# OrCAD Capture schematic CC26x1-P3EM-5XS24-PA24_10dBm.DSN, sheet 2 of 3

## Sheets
2 CC26x1-P3EM-5XS24-PA24: size A4

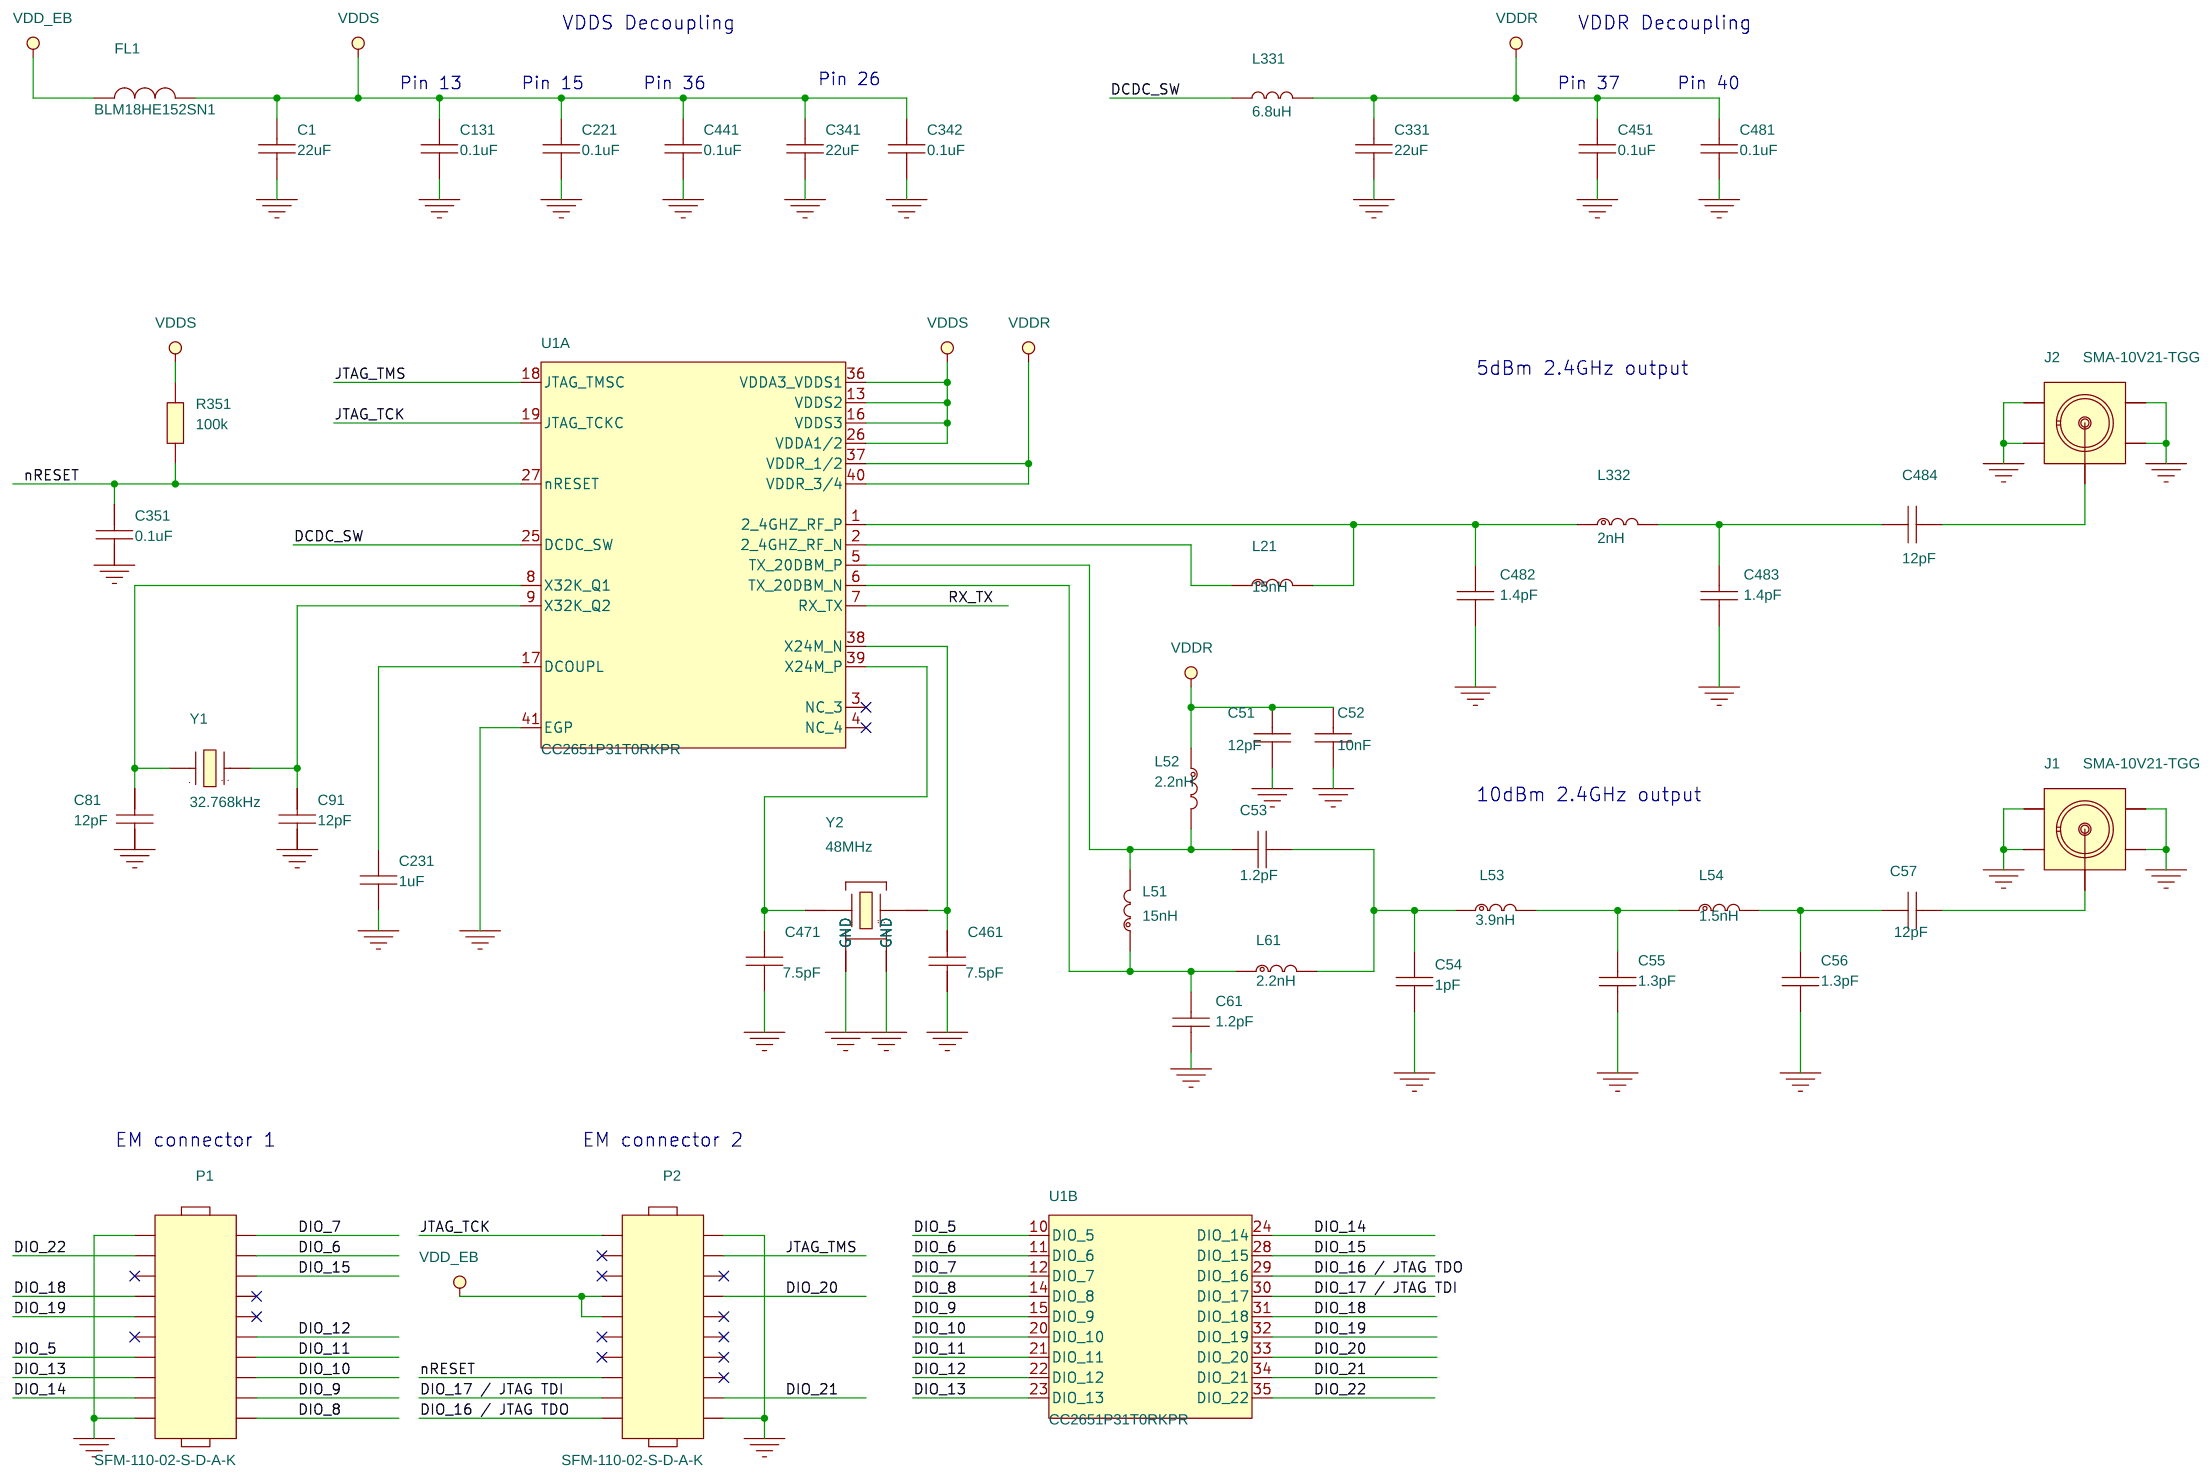
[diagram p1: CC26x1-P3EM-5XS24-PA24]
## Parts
C1  22uF  [CAPC1608X100A2N]
C51  12pF  [CAPC1005X60B2N]
C52  10nF  [CAPC1005X60B2N]
C53  1.2pF  [CAPC1005X60B2N]
C54  1pF  [CAPC1005X60B2N]
C55  1.3pF  [CAPC1005X60B2N]
C56  1.3pF  [CAPC1005X60B2N]
C57  12pF  [CAPC1005X60B2N]
C61  1.2pF  [CAPC1005X60B2N]
C81  12pF  [CAPC1005X60B2N]
C91  12pF  [CAPC1005X60B2N]
C131  0.1uF  [CAPC1005X60B2N]
C221  0.1uF  [CAPC1005X60B2N]
C231  1uF  [CAPC1005X60B2N]
C331  22uF  [CAPC1608X100A2N]
C341  22uF  [CAPC1608X100A2N]
C342  0.1uF  [CAPC1005X60B2N]
C351  0.1uF  [CAPC1005X60B2N]
C441  0.1uF  [CAPC1005X60B2N]
C451  0.1uF  [CAPC1005X60B2N]
C461  7.5pF  [CAPC1005X60B2N]
C471  7.5pF  [CAPC1005X60B2N]
C481  0.1uF  [CAPC1005X60B2N]
C482  1.4pF  [CAPC1005X60B2N]
C483  1.4pF  [CAPC1005X60B2N]
C484  12pF  [CAPC1005X60B2N]
FL1  BLM18HE152SN1  [FIL_BLM18HE152SN1DN]
J1  SMA-10V21-TGG  [HUSTSAN_SMA10V21TGGAN]
J2  SMA-10V21-TGG  [HUSTSAN_SMA10V21TGGAN]
L21  15nH  [INDC1005X60C2N]
L51  15nH  [INDC1005X60C2N]
L52  2.2nH  [INDC1005X60D2N]
L53  3.9nH  [INDC1005X60D2N]
L54  1.5nH  [INDC1005X60D2N]
L61  2.2nH  [INDC1005X60D2N]
L331  6.8uH  [INDC2012X150A2N]
L332  2nH  [INDC1005X60D2N]
P1  SFM-110-02-S-D-A-K  [SAMTEC_SFM11002AN]
P2  SFM-110-02-S-D-A-K  [SAMTEC_SFM11002AN]
R351  100k  [RESC1005X40B2N]
U1  CC2651P31T0RKPR  [QFNFC40P500X500X100-41A2N]  (sections A,B)
Y1  32.768kHz  [XTAL_TZ1166C_B2N]
Y2  48MHz  [OSCCC200X160X50-4A2N]

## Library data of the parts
C1 C331 C341 = CAPACITOR: CAPACITOR, CERAMIC X6S, 22uF, 6.3V, -20%/+20%, -55DEGC/+105DEGC, 0603, SMD; ALT_SYMBOLS: CAPC1608X100A2L,CAPC1608X100A2M; Additional Datasheet URL: https://search.murata.co.jp/Ceramy/image/img/A01X/G101/ENG/GRM188C80J226ME15-02A.pdf; AutoDoc File: https://notefied-dynamic-precision.com/DB/Apps/Desktop/Item/Object.aspx?id=104385; BU Name: DYNAMIC PRECISION GDANSK; Budget Currency: EUR; Budget Price: 0.062; Budgetary Price: 0.07648 USD; Client Status: UNDER_REVIEW; Datasheet URL: https://www.murata.com/-/media/webrenewal/support/library/catalog/products/capacitor/mlcc/c02e.ashx; Datasheet URL 1: http://psearch.murata.com/capacitor/product/GRM188R60J226MEA0%23.pdf; Datasheet URL 2: http://search.murata.co.jp/Ceramy/image/img/w_hinm/L0005E.pdf; Definied Quality: INDUSTRIAL; Dielectric Type: X6S; Esd Level: N/A; Lead Time: 15; LifeCycle Status: ACTIVE; MPN: GRM188R60J226MEA0D; MPN Status: ACTIVE; Manufacturer: MURATA; Mass: 0.0091g; Max Oper Temp: +85DEGC; Max Tol: +20%; Maximum Operating Temperature: +105DEGC; Maximum Tolerance: +20%; Min Oper Temp: -55DEGC; Min Tol: -20%; Minimum Operating Temperature: -55DEGC; Minimum Tolerance: -20%; Mounting Type: SMD; NOTE Status: PREFERRED; NOTEfied URL: https://notefied-dynamic-precision.com/NOTEfiedWebInterface/part/show?partNumber=02-09737; PCB Package: 0603; Packing Size: 4000; Packing Type: Tape & Reel; Part Number: 02-09737; Part Type: Capacitor|CERAMIC|0603|STANDARD; REACH/SVHC Compliance: Compliant; REACH/SVHC Details: SVHC List Version Jan 16, 2020; REACH/SVHC Source: REACH Declaration; REACH/SVHC Status: Unaffected; REACH/SVHC_COMPLIANCE: COMPLIANT; REACH/SVHC_DETAILS: SVHC LIST VERSION Dec 17, 2015; REACH/SVHC_SOURCE: REACH DECLARATION; REACH/SVHC_STATUS: UNAFFECTED; ROHS: Compliant; Rated Current: N/A; Rated Voltage: 6.3V; Revision: R002; RoHS Status: ROHS_COMPLIANT; Rtd Voltage: 6.3V; Status: Released; Texas Part Status: Under Review; Type: Capacitor; Vendor: MURATA; Vendor Part Number: GRM188C80J226ME15D; Vendor Part Status: Active; WEIGHT: 0.0091g
C51 = CAPACITOR: CAPACITOR, CERAMIC C0G/NP0, 12pF, 50V, -5%/+5%, -55DEGC/+125DEGC, 0402, SMD; Additional Datasheet URL: https://search.murata.co.jp/Ceramy/image/img/A01X/G101/ENG/GJM1555C1H120JB01-01.pdf; AutoDoc File: https://notefied-dynamic-precision.com/DB/Apps/Desktop/Item/Object.aspx?id=113345; BU Name: TEXAS INSTRUMENTS NORWAY; Budget Currency: EUR; Budget Price: 0.007; Datasheet URL: https://www.murata.com/-/media/webrenewal/support/library/catalog/products/capacitor/mlcc/c02e.ashx; Datasheet URL 1: http://psearch.murata.com/capacitor/product/GRM1555C1H120JA01%23.pdf; Datasheet URL 2: http://search.murata.co.jp/Ceramy/image/img/w_hinm/L0005E.pdf; Dielectric Type: C0G/NP0; Mass: 0.0016g; Max Oper Temp: +125DEGC; Max Tol: +5%; Maximum Operating Temperature: +125DEGC; Maximum Tolerance: +5%; Min Oper Temp: -55DEGC; Min Tol: -5%; Minimum Operating Temperature: -55DEGC; Minimum Tolerance: -5%; Mounting Type: SMD; NOTEfied URL: https://notefied-dynamic-precision.com/NOTEfiedWebInterface/part/show?partNumber=02-09704; PCB Package: 0402; Packing Size: 10000; Packing Type: Tape & Reel; Part Number: 02-09704; Part Type: Capacitor|CERAMIC|0402|STANDARD; REACH/SVHC Compliance: Compliant; REACH/SVHC Details: SVHC List Version Jan 16, 2020; REACH/SVHC Source: REACH Declaration; REACH/SVHC Status: Unaffected; REACH/SVHC_COMPLIANCE: COMPLIANT; REACH/SVHC_DETAILS: SVHC LIST VERSION Dec 17, 2015; REACH/SVHC_SOURCE: REACH DECLARATION; REACH/SVHC_STATUS: UNAFFECTED; ROHS: Compliant; Rated Voltage: 50V; Revision: R003; RoHS Status: ROHS_COMPLIANT; Rtd Voltage: 50V; Status: Released; Texas Part Status: Under Review; Type: Capacitor; Vendor: MURATA; Vendor Part Number: GJM1555C1H120JB01D; Vendor Part Status: Active; Weight: 0.0016g
C52 = CAPACITOR: CAPACITOR, CERAMIC X7R, 10nF, 50V, -20%/+20%, -55DEGC/+125DEGC, 0402, SMD; Additional Datasheet URL: https://search.murata.co.jp/Ceramy/image/img/A01X/G101/ENG/GRM155R71H103MA88-01A.pdf; AutoDoc File: https://notefied-dynamic-precision.com/DB/Apps/Desktop/Item/Object.aspx?id=114570; BU Name: TEXAS INSTRUMENTS NORWAY; Budget Currency: EUR; Budget Price: 0.003; Client Status: UNDER_REVIEW; Datasheet URL: https://www.murata.com/-/media/webrenewal/support/library/catalog/products/capacitor/mlcc/c02e.ashx; Datasheet URL 1: http://psearch.murata.com/capacitor/product/GRM155R71E103KA01%23.pdf; Datasheet URL 2: http://search.murata.co.jp/Ceramy/image/img/w_hinm/L0005E.pdf; Dielectric Type: X7R; Mass: 0.0016g; Max Oper Temp: +125DEGC; Max Tol: +10%; Maximum Operating Temperature: +125DEGC; Maximum Tolerance: +20%; Min Oper Temp: -55DEGC; Min Tol: -10%; Minimum Operating Temperature: -55DEGC; Minimum Tolerance: -20%; Mounting Type: SMD; NOTEfied URL: https://notefied-dynamic-precision.com/NOTEfiedWebInterface/part/show?partNumber=02-09722; PCB Package: 0402; Packing Size: 10000; Packing Type: Tape & Reel; Part Number: 02-09722; Part Type: Capacitor|CERAMIC|0402|STANDARD; REACH/SVHC Compliance: Compliant; REACH/SVHC Details: SVHC List Version Jan 16, 2020; REACH/SVHC Source: REACH Declaration; REACH/SVHC Status: Unaffected; REACH/SVHC_COMPLIANCE: COMPLIANT; REACH/SVHC_DETAILS: SVHC LIST VERSION Jun 20, 2016; REACH/SVHC_SOURCE: REACH DECLARATION; REACH/SVHC_STATUS: UNAFFECTED; ROHS: Compliant; Rated Voltage: 50V; Revision: R003; RoHS Status: ROHS_COMPLIANT; Rtd Voltage: 25V; Status: Released; Texas Part Status: Under Review; Type: Capacitor; Vendor: MURATA; Vendor Part Number: GRM155R71H103MA88D; Vendor Part Status: Active; Weight: 0.0016g
C53 C61 = CAPACITOR: CAPACITOR, CERAMIC C0G/NP0, 1.2pF, 50V, -0.1pF/+0.1pF, -55DEGC/+125DEGC, 0402, SMD; Additional Datasheet URL: https://search.murata.co.jp/Ceramy/image/img/A01X/G101/ENG/GJM1555C1H1R2BB01-01.pdf; AutoDoc File: https://notefied-dynamic-precision.com/DB/Apps/Desktop/Item/Object.aspx?id=116143; BU Name: TEXAS INSTRUMENTS NORWAY; Budget Currency: EUR; Budget Price: 0.009; Client Status: UNDER_REVIEW; Datasheet URL: https://www.murata.com/-/media/webrenewal/support/library/catalog/products/capacitor/mlcc/c02e.ashx; Datasheet URL 1: http://psearch.murata.com/capacitor/product/GRM1555C1H1R2BA01%23.pdf; Datasheet URL 2: http://search.murata.co.jp/Ceramy/image/img/w_hinm/L0005E.pdf; Dielectric Type: C0G/NP0; Mass: 0.0016g; Max Oper Temp: +125DEGC; Max Tol: +0.1pF; Maximum Operating Temperature: +125DEGC; Maximum Tolerance: +0.1pF; Min Oper Temp: -55DEGC; Min Tol: -0.1pF; Minimum Operating Temperature: -55DEGC; Minimum Tolerance: -0.1pF; Mounting Type: SMD; NOTEfied URL: https://notefied-dynamic-precision.com/NOTEfiedWebInterface/part/show?partNumber=02-09709; PCB Package: 0402; Packing Size: 10000; Packing Type: Tape & Reel; Part Number: 02-09709; Part Type: Capacitor|CERAMIC|0402|STANDARD; REACH/SVHC Compliance: Compliant; REACH/SVHC Details: SVHC List Version Jan 16, 2020; REACH/SVHC Source: REACH Declaration; REACH/SVHC Status: Unaffected; REACH/SVHC_COMPLIANCE: COMPLIANT; REACH/SVHC_DETAILS: SVHC LIST VERSION Jun 20, 2016; REACH/SVHC_SOURCE: REACH DECLARATION; REACH/SVHC_STATUS: UNAFFECTED; ROHS: Compliant; Rated Voltage: 50V; Revision: R003; RoHS Status: ROHS_COMPLIANT; Rtd Voltage: 50V; Status: Released; Texas Part Status: Under Review; Type: Capacitor; Vendor: MURATA; Vendor Part Number: GJM1555C1H1R2BB01D; Vendor Part Status: Active; Weight: 0.0016g
C54 = CAPACITOR: CAPACITOR, CERAMIC C0G/NP0, 1pF, 50V, -0.25pF/+0.25pF, -55DEGC/+125DEGC, 0402, SMD; Additional Datasheet URL: https://search.murata.co.jp/Ceramy/image/img/A01X/G101/ENG/GJM1555C1H1R0CB01-01.pdf; AutoDoc File: https://notefied-dynamic-precision.com/DB/Apps/Desktop/Item/Object.aspx?id=90851; BU Name: TEXAS INSTRUMENTS NORWAY; Budget Currency: EUR; Budget Price: 0.017; Client Status: UNDER_REVIEW; Datasheet URL: https://www.murata.com/-/media/webrenewal/support/library/catalog/products/capacitor/ceramiccapacitor/c02e.ashx; Datasheet URL 1: http://psearch.murata.com/capacitor/product/GRM1555C1HR80BA01%23.pdf; Datasheet URL 2: http://search.murata.co.jp/Ceramy/image/img/w_hinm/L0005E.pdf; Dielectric Type: C0G/NP0; Mass: 0.0016g; Max Oper Temp: +125DEGC; Max Tol: +0.1pF; Maximum Operating Temperature: +125DEGC; Maximum Tolerance: +0.25pF; Min Oper Temp: -55DEGC; Min Tol: -0.1pF; Minimum Operating Temperature: -55DEGC; Minimum Tolerance: -0.25pF; Mounting Type: SMD; NOTEfied URL: https://notefied-dynamic-precision.com/NOTEfiedWebInterface/part/show?partNumber=02-09706; PCB Package: 0402; Packing Size: 10000; Packing Type: Tape & Reel; Part Number: 02-09706; Part Type: Capacitor|CERAMIC|0402|STANDARD; REACH/SVHC Compliance: Compliant; REACH/SVHC Details: SVHC List Version Jan 16, 2020; REACH/SVHC Source: REACH Declaration; REACH/SVHC Status: Unaffected; REACH/SVHC_COMPLIANCE: COMPLIANT; REACH/SVHC_DETAILS: SVHC LIST VERSION Dec 17, 2015; REACH/SVHC_SOURCE: REACH DECLARATION; REACH/SVHC_STATUS: UNAFFECTED; ROHS: Compliant; Rated Voltage: 50V; Revision: R006; RoHS Status: ROHS_COMPLIANT; Rtd Voltage: 50V; Status: Released; Texas Part Status: Under Review; Type: Capacitor; Vendor: MURATA; Vendor Part Number: GJM1555C1H1R0CB01D; Vendor Part Status: Active; Weight: 0.0016g
C55 = CAPACITOR: CAPACITOR, CERAMIC C0G/NP0, 1.3pF, 50V, -0.05pF/+0.05pF, -55DEGC/+125DEGC, 0402, SMD; Additional Datasheet URL: https://search.murata.co.jp/Ceramy/image/img/A01X/G101/ENG/GJM1555C1H1R3WB01-01.pdf; AutoDoc File: https://notefied-dynamic-precision.com/DB/Apps/Desktop/Item/Object.aspx?id=116145; BU Name: TEXAS INSTRUMENTS NORWAY; Budgetary Price: 0.04725 USD; Client Status: UNDER_REVIEW; Country of Origin: Japan; Datasheet URL: https://www.murata.com/-/media/webrenewal/support/library/catalog/products/capacitor/mlcc/c02e.ashx?la=en-gb; Datasheet URL 1: http://www.murata.com/~/media/webrenewal/support/library/catalog/products/capacitor/mlcc/c02e.ashx?la=en-gb; Datasheet URL 2: N/A; Dielectric Type: C0G/NP0; Lead Time: 11; Mass: 0.0016g; Max Oper Temp: +125DEGC; Max Tol: +0.1pF; Maximum Operating Temperature: +125DEGC; Maximum Tolerance: +0.05pF; Min Oper Temp: -55DEGC; Min Tol: -0.1pF; Minimum Operating Temperature: -55DEGC; Minimum Tolerance: -0.05pF; Mounting Type: SMD; NOTEfied URL: https://notefied-dynamic-precision.com/NOTEfiedWebInterface/part/show?partNumber=02-06572; PCB Package: 0402; Packing Size: 10000; Packing Type: Tape & Reel; Part Number: 02-06572; Part Type: Capacitor|CERAMIC|0402|STANDARD; REACH/SVHC Compliance: Compliant; REACH/SVHC Details: SVHC List Version Jul 08, 2021; REACH/SVHC Source: REACH Declaration; REACH/SVHC Status: Unaffected; REACH/SVHC_COMPLIANCE: COMPLIANT; REACH/SVHC_DETAILS: SVHC LIST VERSION Jun 20, 2016; REACH/SVHC_SOURCE: REACH DECLARATION; REACH/SVHC_STATUS: UNAFFECTED; ROHS: Compliant; Rated Voltage: 50V; Revision: R010; RoHS Status: ROHS_COMPLIANT; Rtd Voltage: 50V; Status: Released; Texas Part Status: Under Review; Type: Capacitor; Vendor: MURATA; Vendor Part Number: GJM1555C1H1R3WB01D; Vendor Part Status: Active
C56 = CAPACITOR: CAPACITOR, CERAMIC C0G/NP0, 1.3pF, 50V, -0.05pF/+0.05pF, -55DEGC/+125DEGC, 0402, SMD; Additional Datasheet URL: https://search.murata.co.jp/Ceramy/image/img/A01X/G101/ENG/GJM1555C1H1R3WB01-01A.pdf; AutoDoc File: https://notefied-dynamic-precision.com/DB/Apps/Desktop/Item/Object.aspx?id=116145; BU Name: TEXAS INSTRUMENTS NORWAY; Budgetary Price: 0.04725 USD; Client Status: UNDER_REVIEW; Country of Origin: Japan; Datasheet URL: https://www.murata.com/-/media/webrenewal/support/library/catalog/products/capacitor/ceramiccapacitor/c02e.ashx?la=en-gb&cvid=20210120024548000000; Datasheet URL 1: http://www.murata.com/~/media/webrenewal/support/library/catalog/products/capacitor/mlcc/c02e.ashx?la=en-gb; Datasheet URL 2: N/A; Dielectric Type: C0G/NP0; Lead Time: 11; Mass: 0.0016g; Max Oper Temp: +125DEGC; Max Tol: +0.1pF; Maximum Operating Temperature: +125DEGC; Maximum Tolerance: +0.05pF; Min Oper Temp: -55DEGC; Min Tol: -0.1pF; Minimum Operating Temperature: -55DEGC; Minimum Tolerance: -0.05pF; Mounting Type: SMD; NOTEfied URL: https://notefied-dynamic-precision.com/NOTEfiedWebInterface/part/show?partNumber=02-06572; PCB Package: 0402; Packing Size: 10000; Packing Type: Tape & Reel; Part Number: 02-06572; Part Type: Capacitor|CERAMIC|0402|STANDARD; REACH/SVHC Compliance: Compliant; REACH/SVHC Details: SVHC List Version Jul 08, 2021; REACH/SVHC Source: REACH Declaration; REACH/SVHC Status: Unaffected; REACH/SVHC_COMPLIANCE: COMPLIANT; REACH/SVHC_DETAILS: SVHC LIST VERSION Jun 20, 2016; REACH/SVHC_SOURCE: REACH DECLARATION; REACH/SVHC_STATUS: UNAFFECTED; ROHS: Compliant; Rated Voltage: 50V; Revision: R011; RoHS Status: ROHS_COMPLIANT; Rtd Voltage: 50V; Status: Released; Texas Part Status: Under Review; Type: Capacitor; Vendor: MURATA; Vendor Part Number: GJM1555C1H1R3WB01D; Vendor Part Status: Active
C57 = CAPACITOR: CAPACITOR, CERAMIC C0G/NP0, 12pF, 50V, -5%/+5%, -55DEGC/+125DEGC, 0402, SMD; Additional Datasheet URL: https://search.murata.co.jp/Ceramy/image/img/A01X/G101/ENG/GJM1555C1H120JB01-01.pdf; AutoDoc File: https://notefied-dynamic-precision.com/DB/Apps/Desktop/Item/Object.aspx?id=113346; BU Name: TEXAS INSTRUMENTS NORWAY; Budget Currency: EUR; Budget Price: 0.007; Datasheet URL: https://www.murata.com/-/media/webrenewal/support/library/catalog/products/capacitor/ceramiccapacitor/c02e.ashx; Datasheet URL 1: http://psearch.murata.com/capacitor/product/GRM1555C1H6R8CA01%23.pdf; Datasheet URL 2: http://search.murata.co.jp/Ceramy/image/img/w_hinm/L0005E.pdf; Dielectric Type: C0G/NP0; Mass: 0.0016g; Max Oper Temp: +125DEGC; Max Tol: +0.25pF; Maximum Operating Temperature: +125DEGC; Maximum Tolerance: +5%; Min Oper Temp: -55DEGC; Min Tol: -0.25pF; Minimum Operating Temperature: -55DEGC; Minimum Tolerance: -5%; Mounting Type: SMD; NOTEfied URL: https://notefied-dynamic-precision.com/NOTEfiedWebInterface/part/show?partNumber=02-09704; PCB Package: 0402; Packing Size: 10000; Packing Type: Tape & Reel; Part Number: 02-09704; Part Type: Capacitor|CERAMIC|0402|STANDARD; REACH/SVHC Compliance: Compliant; REACH/SVHC Details: SVHC List Version Jan 16, 2020; REACH/SVHC Source: REACH Declaration; REACH/SVHC Status: Unaffected; REACH/SVHC_COMPLIANCE: COMPLIANT; REACH/SVHC_DETAILS: SVHC LIST VERSION Dec 17, 2015; REACH/SVHC_SOURCE: REACH DECLARATION; REACH/SVHC_STATUS: UNAFFECTED; ROHS: Compliant; Rated Voltage: 50V; Revision: R006; RoHS Status: ROHS_COMPLIANT; Rtd Voltage: 50V; Status: Released; Texas Part Status: Under Review; Type: Capacitor; Vendor: MURATA; Vendor Part Number: GJM1555C1H120JB01D; Vendor Part Status: Active; Weight: 0.0016g
C81 C91 C484 = CAPACITOR: CAPACITOR, CERAMIC C0G/NP0, 12pF, 50V, -5%/+5%, -55DEGC/+125DEGC, 0402, SMD; Additional Datasheet URL: https://search.murata.co.jp/Ceramy/image/img/A01X/G101/ENG/GJM1555C1H120JB01-01.pdf; AutoDoc File: https://notefied-dynamic-precision.com/DB/Apps/Desktop/Item/Object.aspx?id=113345; BU Name: TEXAS INSTRUMENTS NORWAY; Budget Currency: EUR; Budget Price: 0.007; Datasheet URL: https://www.murata.com/-/media/webrenewal/support/library/catalog/products/capacitor/mlcc/c02e.ashx; Datasheet URL 1: http://psearch.murata.com/capacitor/product/GRM1555C1H120JA01%23.pdf; Datasheet URL 2: http://search.murata.co.jp/Ceramy/image/img/w_hinm/L0005E.pdf; Definied Quality: INDUSTRIAL; Dielectric Type: C0G/NP0; Esd Level: N/A; MPN: GRM1555C1H120JA01D; MPN Status: ACTIVE; MSL: 1; MTBF: N/A; MTBF Standard: N/A; Manufacturer: MURATA; Mass: 0.0016g; Max Oper Temp: +125DEGC; Max Tol: +5%; Maximum Operating Temperature: +125DEGC; Maximum Tolerance: +5%; Min Oper Temp: -55DEGC; Min Tol: -5%; Minimum Operating Temperature: -55DEGC; Minimum Tolerance: -5%; Mounting Type: SMD; NOTE Status: PREFERRED; NOTEfied URL: https://notefied-dynamic-precision.com/NOTEfiedWebInterface/part/show?partNumber=02-09704; Old Footprint: CAPC1005X60N; PCB Package: 0402; Packing Size: 10000; Packing Type: Tape & Reel; Part Number: 02-09704; Part Type: Capacitor|CERAMIC|0402|STANDARD; REACH/SVHC Compliance: Compliant; REACH/SVHC Details: SVHC List Version Jan 16, 2020; REACH/SVHC Source: REACH Declaration; REACH/SVHC Status: Unaffected; REACH/SVHC_COMPLIANCE: COMPLIANT; REACH/SVHC_DETAILS: SVHC LIST VERSION Dec 17, 2015; REACH/SVHC_SOURCE: REACH DECLARATION; REACH/SVHC_STATUS: UNAFFECTED; ROHS: Compliant; Rated Voltage: 50V; Revision: R003; RoHS Status: ROHS_COMPLIANT; Rtd Voltage: 50V; Status: Released; Texas Part Status: Under Review; Type: Capacitor; Vendor: MURATA; Vendor Part Number: GJM1555C1H120JB01D; Vendor Part Status: Active; WEIGHT: 0.0016g
C131 C221 C351 C441 C451 C481 = CAPACITOR: CAPACITOR, CERAMIC X7R, 0.1uF, 25V, -10%/+10%, -55DEGC/+125DEGC, 0402, SMD; Additional Datasheet URL: https://search.murata.co.jp/Ceramy/image/img/A01X/G101/ENG/GRM155R71E104KE14-01A.pdf; AutoDoc File: https://notefied-dynamic-precision.com/DB/Apps/Desktop/Item/Object.aspx?id=115293; BU Name: TEXAS INSTRUMENTS NORWAY; Budgetary Price: 0.00567 USD; Client Status: UNDER_REVIEW; Datasheet URL: https://www.murata.com/-/media/webrenewal/support/library/catalog/products/capacitor/mlcc/c02e.ashx?la=en-gb; Datasheet URL 1: http://psearch.en.murata.com/capacitor/product/GRM155R71E104KE14%23.pdf; Datasheet URL 2: http://search.murata.co.jp/Ceramy/image/img/w_hinm/L0005E.pdf; Dielectric Type: X7R; Lead Time: 11; LifeCycle Status: ACTIVE; MPN: GRM155R70J104KA01D; MPN Status: ACTIVE; Manufacturer: MURATA; Mass: 0.0016g; Max Oper Temp: +125DEGC; Max Tol: +10%; Maximum Operating Temperature: +125DEGC; Maximum Tolerance: +10%; Min Oper Temp: -55DEGC; Min Tol: -10%; Minimum Operating Temperature: -55DEGC; Minimum Tolerance: -10%; Mounting Type: SMD; NOTE Status: PREFERRED; NOTEfied URL: https://notefied-dynamic-precision.com/NOTEfiedWebInterface/part/show?partNumber=02-07861; Old Footprint: CAPC1005X60N,0402; PCB Package: 0402; Packing Size: 10000; Packing Type: Tape & Reel; Part Number: 02-07861; Part Type: Capacitor|CERAMIC|0402|STANDARD; REACH/SVHC Compliance: Compliant; REACH/SVHC Details: SVHC List Version Jul 7, 2017; REACH/SVHC Source: REACH Declaration; REACH/SVHC Status: Unaffected; REACH/SVHC_COMPLIANCE: COMPLIANT; REACH/SVHC_DETAILS: SVHC LIST VERSION Jun 20, 2016; REACH/SVHC_SOURCE: REACH DECLARATION; REACH/SVHC_STATUS: UNAFFECTED; ROHS: Compliant; Rated Voltage: 25V; Revision: R021; RoHS Status: ROHS_COMPLIANT; Rtd Voltage: 25V; Status: Released; Texas Part Status: Under Review; Type: Capacitor; Vendor: MURATA; Vendor Part Number: GRM155R71E104KE14D; Vendor Part Status: Active; WEIGHT: 0.0016g
C231 = CAPACITOR: CAPACITOR, CERAMIC X6S, 1uF, 16V, -10%/+10%, -55DEGC/+105DEGC, 0402, SMD; Additional Datasheet URL: https://search.murata.co.jp/Ceramy/image/img/A01X/G101/ENG/GRM155C81C105KE11-01A.pdf; AutoDoc File: https://notefied-dynamic-precision.com/DB/Apps/Desktop/Item/Object.aspx?id=115295; BU Name: TEXAS INSTRUMENTS NORWAY; Client Status: UNDER_REVIEW; Datasheet URL: https://www.murata.com/-/media/webrenewal/support/library/catalog/products/capacitor/mlcc/c02e.ashx; Datasheet URL 1: http://psearch.en.murata.com/capacitor/product/GRM155R61C105KA12%23.pdf; Datasheet URL 2: http://search.murata.co.jp/Ceramy/image/img/w_hinm/L0005E.pdf; Definied Quality: INDUSTRIAL; Dielectric Type: X6S; Esd Level: N/A; MPN: GRM155R61A105KE15D; MPN Status: ACTIVE; MSL: 1; MTBF: N/A; MTBF Standard: N/A; Manufacturer: MURATA; Mass: 0.0016g; Max Oper Temp: +85DEGC; Max Tol: +10%; Maximum Operating Temperature: +105DEGC; Maximum Tolerance: +10%; Min Oper Temp: -55DEGC; Min Tol: -10%; Minimum Operating Temperature: -55DEGC; Minimum Tolerance: -10%; Mounting Type: SMD; NOTE Status: PREFERRED; NOTEfied URL: https://notefied-dynamic-precision.com/NOTEfiedWebInterface/part/show?partNumber=02-09724; Old Footprint: CAPC1005X60N,0402; PCB Package: 0402; Packing Size: 10000; Packing Type: Tape & Reel; Part Number: 02-09724; Part Type: Capacitor|CERAMIC|0402|STANDARD; REACH/SVHC Compliance: Compliant; REACH/SVHC Details: SVHC List Version Jan 16, 2020; REACH/SVHC Source: REACH Declaration; REACH/SVHC Status: Unaffected; REACH/SVHC_COMPLIANCE: COMPLIANT; REACH/SVHC_DETAILS: SVHC LIST VERSION Jun 20, 2016; REACH/SVHC_SOURCE: REACH DECLARATION; REACH/SVHC_STATUS: UNAFFECTED; ROHS: Compliant; Rated Voltage: 16V; Revision: R003; RoHS Status: ROHS_COMPLIANT; Rtd Voltage: 16V; Status: Released; Texas Part Status: Under Review; Type: Capacitor; Vendor: MURATA; Vendor Part Number: GRM155C81C105KE11D; Vendor Part Status: Active; WEIGHT: 0.0016g
C342 = CAPACITOR: CAPACITOR, CERAMIC X7R, 0.1uF, 25V, -10%/+10%, -55DEGC/+125DEGC, 0402, SMD; Additional Datasheet URL: https://search.murata.co.jp/Ceramy/image/img/A01X/G101/ENG/GRM155R71E104KE14-01A.pdf; AutoDoc File: https://notefied-dynamic-precision.com/DB/Apps/Desktop/Item/Object.aspx?id=115293; BU Name: TEXAS INSTRUMENTS NORWAY; Budgetary Price: 0.00567 USD; Cage Code: C0151; Client Status: UNDER_REVIEW; Datasheet URL: https://www.murata.com/-/media/webrenewal/support/library/catalog/products/capacitor/mlcc/c02e.ashx?la=en-gb; Datasheet URL 1: http://psearch.en.murata.com/capacitor/product/GRM155R71E104KE14%23.pdf; Datasheet URL 2: http://search.murata.co.jp/Ceramy/image/img/w_hinm/L0005E.pdf; Definied Quality: INDUSTRIAL; Dielectric Type: X7R; Esd Level: N/A; Lead Time: 11; MPN: GRM188R71E104KA01D; MPN Status: NRND; MSL: 1; MTBF: N/A; MTBF Standard: N/A; Manufacturer: MURATA; Mass: 0.0016g; Max Oper Temp: +125DEGC; Max Tol: +10%; Maximum Operating Temperature: +125DEGC; Maximum Tolerance: +10%; Min Oper Temp: -55DEGC; Min Tol: -10%; Minimum Operating Temperature: -55DEGC; Minimum Tolerance: -10%; Mounting Type: SMD; NOTE Status: PREFERRED; NOTEfied URL: https://notefied-dynamic-precision.com/NOTEfiedWebInterface/part/show?partNumber=02-07861; Old Footprint: CAPC1608X90N,0603; PCB Package: 0402; Packing Size: 10000; Packing Type: Tape & Reel; Part Number: 02-07861; Part Type: Capacitor|CERAMIC|0402|STANDARD; REACH/SVHC Compliance: Compliant; REACH/SVHC Details: SVHC List Version Jul 7, 2017; REACH/SVHC Source: REACH Declaration; REACH/SVHC Status: Unaffected; REACH/SVHC_COMPLIANCE: COMPLIANT; REACH/SVHC_DETAILS: SVHC LIST VERSION Jun 20, 2016; REACH/SVHC_SOURCE: REACH DECLARATION; REACH/SVHC_STATUS: UNAFFECTED; ROHS: Compliant; Rated Voltage: 25V; Revision: R021; RoHS Status: ROHS_COMPLIANT; Rtd Voltage: 25V; Status: Released; Texas Part Status: Under Review; Type: Capacitor; Vendor: MURATA; Vendor Part Number: GRM155R71E104KE14D; Vendor Part Status: Active; WEIGHT: 0.0016g
C461 C471 = CAPACITOR: CAPACITOR, CERAMIC C0G/NP0, 7.5pF, 50V, -0.25pF/+0.25pF, -55DEGC/+125DEGC, 0402, SMD; Additional Datasheet URL: https://search.murata.co.jp/Ceramy/image/img/A01X/G101/ENG/GJM1555C1H7R5CB01-01.pdf; Datasheet URL: https://www.murata.com/-/media/webrenewal/support/library/catalog/products/capacitor/mlcc/c02e.ashx; Dielectric Type: C0G/NP0; Mass: 0.0016g; Maximum Operating Temperature: +125DEGC; Maximum Tolerance: +0.25pF; Minimum Operating Temperature: -55DEGC; Minimum Tolerance: -0.25pF; Mounting Type: SMD; NOTEfied URL: https://notefied-dynamic-precision.com/NOTEfiedWebInterface/part/show?partNumber=02-09718; PCB Package: 0402; Packing Size: 10000; Packing Type: Tape & Reel; Part Number: 02-09718; Part Type: Capacitor|CERAMIC|0402|STANDARD; REACH/SVHC Compliance: Compliant; REACH/SVHC Details: SVHC List Version Jan 16, 2020; REACH/SVHC Source: REACH Declaration; REACH/SVHC Status: Unaffected; ROHS: Compliant; Rated Voltage: 50V; Revision: R003; Status: Released; Texas Part Status: Under Review; Type: Capacitor; Vendor: MURATA; Vendor Part Number: GJM1555C1H7R5CB01D; Vendor Part Status: Active
C482 C483 = CAPACITOR: CAPACITOR, CERAMIC C0G/NP0, 1.4pF, 50V, -0.1pF/+0.1pF, -55DEGC/+125DEGC, 0402, SMD; Additional Datasheet URL: https://search.murata.co.jp/Ceramy/image/img/A01X/G101/ENG/GJM1555C1H1R4BB01-01.pdf; AutoDoc File: https://notefied-dynamic-precision.com/DB/Apps/Desktop/Item/Object.aspx?id=116143; BU Name: TEXAS INSTRUMENTS NORWAY; Budget Currency: EUR; Budget Price: 0.009; Client Status: UNDER_REVIEW; Datasheet URL: https://www.murata.com/-/media/webrenewal/support/library/catalog/products/capacitor/ceramiccapacitor/c02e.ashx; Datasheet URL 1: http://psearch.murata.com/capacitor/product/GRM1555C1H1R2BA01%23.pdf; Datasheet URL 2: http://search.murata.co.jp/Ceramy/image/img/w_hinm/L0005E.pdf; Dielectric Type: C0G/NP0; Mass: 0.0016g; Max Oper Temp: +125DEGC; Max Tol: +0.1pF; Maximum Operating Temperature: +125DEGC; Maximum Tolerance: +0.1pF; Min Oper Temp: -55DEGC; Min Tol: -0.1pF; Minimum Operating Temperature: -55DEGC; Minimum Tolerance: -0.1pF; Mounting Type: SMD; NOTEfied URL: https://notefied-dynamic-precision.com/NOTEfiedWebInterface/part/show?partNumber=02-10046; PCB Package: 0402; Packing Size: 10000; Packing Type: Tape & Reel; Part Number: 02-10046; Part Type: Capacitor|CERAMIC|0402|STANDARD; REACH/SVHC Compliance: Compliant; REACH/SVHC Details: SVHC List Version Jun 25, 2020; REACH/SVHC Source: REACH Declaration; REACH/SVHC Status: Unaffected; REACH/SVHC_COMPLIANCE: COMPLIANT; REACH/SVHC_DETAILS: SVHC LIST VERSION Jun 20, 2016; REACH/SVHC_SOURCE: REACH DECLARATION; REACH/SVHC_STATUS: UNAFFECTED; ROHS: Compliant; Rated Voltage: 50V; Revision: R005; RoHS Status: ROHS_COMPLIANT; Rtd Voltage: 50V; Status: Released; Texas Part Status: Under Review; Type: Capacitor; Vendor: MURATA; Vendor Part Number: GJM1555C1H1R4BB01D; Vendor Part Status: Active; Weight: 0.0016g
FL1 = FILTER_2PIN: FILTER, EMI, FERRITE BEAD, 1500@100MHz, -25%/+25%, -55DEGC/+125DEGC, 0603, SMD; ALT_SYMBOLS: FIL_BLM18HE152SN1DL,FIL_BLM18HE152SN1DM; Additional Datasheet URL: https://www.murata.com/en-eu/products/productdata/8796741599262/ENFA0004.pdf?1531144803000; AutoDoc File: https://notefied-dynamic-precision.com/DB/Apps/Desktop/Item/Object.aspx?id=85575; BU Name: DYNAMIC PRECISION GDANSK; Budget Currency: EUR; Budget Price: 0.065; Budgetary Price: 0.07 EUR; CLASS: IC; Client Status: UNDER_REVIEW; Country of Origin: Japan,Singapore,Thailand; Datasheet URL: https://www.murata.com/~/media/webrenewal/support/library/catalog/products/emc/emifil/c31e.ashx; Datasheet URL 1: http://search.murata.co.jp/Ceramy/image/img/PDF/ENG/L0110S0101BLM18H.pdf; Datasheet URL 2: http://search.murata.co.jp/Ceramy/image/img/w_hinm/L0110E.pdf; Frequency: 100MHz; Impedance: 1500; Inductance: N/A; Lead Time: 8; MPN: BLM18HE152SN1D; MPN Status: ACTIVE; Manufacturer: MURATA; Mass: 0.006g; Max Oper Temp: +125DEGC; Max Tol: +25%; Maximum Operating Temperature: +125DEGC; Maximum Tolerance: +25%; Min Oper Temp: -55DEGC; Min Tol: -25%; Minimum Operating Temperature: -55DEGC; Minimum Tolerance: -25%; Mounting Type: SMD; NOTE Status: PREFERRED; NOTEfied URL: https://notefied-dynamic-precision.com/NOTEfiedWebInterface/part/show?partNumber=04-00470; PCB Package: 0603; Packing Size: 4000; Packing Type: Tape & Reel; Part Number: 04-00470; Part Type: Filter|EMI|FERRITE BEAD|0603; REACH/SVHC Compliance: Compliant; REACH/SVHC Details: SVHC List Version Jul 7, 2017; REACH/SVHC Source: REACH Declaration; REACH/SVHC Status: Unaffected; REACH/SVHC_COMPLIANCE: COMPLIANT; REACH/SVHC_DETAILS: SVHC LIST VERSION Dec 17, 2015; REACH/SVHC_SOURCE: REACH DECLARATION; REACH/SVHC_STATUS: UNAFFECTED; ROHS: Compliant; Rated Current: 0.5A; Rated Voltage: N/A; Revision: R022; RoHS Status: ROHS_COMPLIANT; Rtd Current: 0.5A; Rtd Voltage: N/A; Status: Released; Texas Part Status: Under Review; Type: Filter; Vendor: MURATA; Vendor Part Number: BLM18HE152SN1D; Vendor Part Status: Active; WEIGHT: 0.006g
J1 J2 = CONN_COAX_1+4: CONNECTOR, COAX, RF, FEMALE, STRAIGHT, 1 PIN, SMD; ALT_SYMBOLS: HUSTSAN_SMA10V21TGGL,HUSTSAN_SMA10V21TGGM; Additional Datasheet URL: http://www.hustsan.com.tw/cgi-bin/productfn/pdt_detail_lst.pl?ProdID=143; AutoDoc File: https://notefied-dynamic-precision.com/DB/Apps/Desktop/Item/Object.aspx?id=84956; BU Name: DYNAMIC PRECISION GDANSK; Budget Currency: N/A; Budget Price: N/A; CLASS: IO; Client Status: UNDER_REVIEW; Country of Origin: Taiwan; Datasheet URL: http://www.hustsan.com.tw/uploaddir/product/SMA-10V21.pdf; Datasheet URL 1: http://www.hustsan.com.tw/uploaddir/product/SMA-10V21.pdf; Datasheet URL 2: http://www.hustsan.com.tw/cgi-bin/productfn/pdt_detail_lst.pl?ProdID=143; FPLIST: HUSTSAN_SMA10V21TGGAN,HUSTSAN_SMA10V21TGGN; MPN Status: ACTIVE; MSL: N/A; Manufacturer: HUS-TSAN; Mass: N/A; Mounting Type: SMD; NOTE Status: PREFERRED; NOTEfied URL: https://notefied-dynamic-precision.com/NOTEfiedWebInterface/part/show?partNumber=06-02188; No Of Pos: 1; Number of Positions: 1; Old Footprint: HUSTSAN_SMA10V21TGGAN,HUSTSAN_SMA10V21TGGN; Packing Size: 350; Packing Type: Tape & Reel; Part Number: 06-02188; Part Type: Connector|COAX|RF; REACH/SVHC Compliance: Compliant; REACH/SVHC Details: SVHC List Version Jun 20, 2016; REACH/SVHC Source: REACH Declaration; REACH/SVHC Status: Unaffected; ROHS: Compliant; Revision: R021; RoHS Status: ROHS_COMPLIANT; Status: Released; Texas Part Status: Under Review; Type: Connector; Vendor: HUS-TSAN; Vendor Part Status: Active; WEIGHT: N/A
L21 L51 = INDUCTOR_HOR_1_2: INDUCTOR, RF, CHIP, NON-MAGNETIC CORE, 15nH, -5%/+5%, 0.3A, -55DEGC/+125DEGC, 0402, SMD; ALT_SYMBOLS: INDC1005X60C2L,INDC1005X60C2M; Additional Datasheet URL: https://search.murata.co.jp/Ceramy/image/img/P02/JELF243B-0010.pdf; Budgetary Price: 0.01872 USD; Country of Origin: Japan,Singapore; Datasheet URL: https://www.murata.com/-/media/webrenewal/support/library/catalog/products/inductor/chip/o05e.ashx?la=en-gb; FPLIST: INDC1005X60C2N,INDC1005X60D2N; Frequency: 2.5GHz; Lead Time: 8; Mass: 0.001g; Maximum Operating Temperature: +125DEGC; Maximum Tolerance: +5%; Minimum Operating Temperature: -55DEGC; Minimum Tolerance: -5%; Mounting Type: SMD; NOTEfied URL: https://notefied-dynamic-precision.com/NOTEfiedWebInterface/part/show?partNumber=03-06637; PCB Package: 0402; Packing Size: 10000; Packing Type: Tape & Reel; Part Number: 03-06637; Part Type: Inductor|RF|CHIP|0402; REACH/SVHC Compliance: Compliant; REACH/SVHC Details: SVHC List Version Jul 7, 2017; REACH/SVHC Source: REACH Declaration; REACH/SVHC Status: Unaffected; ROHS: Compliant; Resistance: 0.32; Revision: R025; Status: Released; Texas Part Status: Under Review; Type: Inductor; Vendor: MURATA; Vendor Part Number: LQG15HS15NJ02D; Vendor Part Status: Active
L52 L61 = INDUCTOR_HOR_1_2: INDUCTOR, RF, CHIP, NON-MAGNETIC CORE, 2.2nH, -0.3nH/+0.3nH, 0.3A, -55DEGC/+125DEGC, 0402, SMD; Additional Datasheet URL: https://search.murata.co.jp/Ceramy/image/img/P02/JELF243B-0010.pdf; AutoDoc File: https://notefied-dynamic-precision.com/DB/Apps/Desktop/Item/Object.aspx?id=113364; BU Name: TEXAS INSTRUMENTS NORWAY; Budget Currency: EUR; Budget Price: 0.031; Budgetary Price: 0.01872 USD; Client Status: UNDER_REVIEW; Core Material: NON-MAGNETIC; Country of Origin: Japan,Singapore; Datasheet URL: https://www.murata.com/-/media/webrenewal/support/library/catalog/products/inductor/chip/o05e.ashx; Datasheet URL 1: http://psearch.murata.com/inductor/product/LQG15HS2N0S02%23.pdf; Datasheet URL 2: http://www.murata.com/~/media/webrenewal/support/library/catalog/products/inductor/chip/o05e.ashx; FPLIST: INDC1005X60C2N,INDC1005X60D2N; Frequency: 6GHz; Lead Time: 8; Mass: 0.001g; Max Oper Temp: +125DEGC; Max Tol: +0.3nH; Maximum Operating Temperature: +125DEGC; Maximum Tolerance: +0.3nH; Min Oper Temp: -55DEGC; Min Tol: -0.3nH; Minimum Operating Temperature: -55DEGC; Minimum Tolerance: -0.3nH; Mounting Type: SMD; NOTEfied URL: https://notefied-dynamic-precision.com/NOTEfiedWebInterface/part/show?partNumber=03-06629; PCB Package: 0402; Packing Size: 10000; Packing Type: Tape & Reel; Part Number: 03-06629; Part Type: Inductor|RF|CHIP|0402; REACH/SVHC_COMPLIANCE: COMPLIANT; REACH/SVHC_DETAILS: SVHC LIST VERSION Dec 17, 2015; REACH/SVHC_SOURCE: REACH DECLARATION; REACH/SVHC_STATUS: UNAFFECTED; ROHS: Compliant; Revision: R023; RoHS Status: ROHS_COMPLIANT; Rtd Current: 0.3A; Status: Released; Texas Part Status: Under Review; Type: Inductor; Vendor: MURATA; Vendor Part Number: LQG15HS2N2S02D; Vendor Part Status: Active; Weight: 0.001g
L53 = INDUCTOR_HOR_1_2: INDUCTOR, RF, CHIP, NON-MAGNETIC CORE, 3.9nH, -0.3nH/+0.3nH, 0.3A, -55DEGC/+125DEGC, 0402, SMD; Additional Datasheet URL: https://search.murata.co.jp/Ceramy/image/img/P02/JELF243B-0010.pdf; AutoDoc File: https://notefied-dynamic-precision.com/DB/Apps/Desktop/Item/Object.aspx?id=116101; BU Name: TEXAS INSTRUMENTS NORWAY; Budget Currency: EUR; Budget Price: 0.031; Budgetary Price: 0.01872 USD; Client Status: UNDER_REVIEW; Core Material: NON-MAGNETIC; Country of Origin: Japan,Singapore; Datasheet URL: https://www.murata.com/-/media/webrenewal/support/library/catalog/products/inductor/chip/o05e.ashx; Datasheet URL 1: http://psearch.murata.com/inductor/product/LQG15HS1N8S02%23.pdf; Datasheet URL 2: http://www.murata.com/~/media/webrenewal/support/library/catalog/products/inductor/chip/o05e.ashx; FPLIST: INDC1005X60C2N,INDC1005X60D2N; Frequency: 6GHz; Lead Time: 8; Mass: 0.001g; Max Oper Temp: +125DEGC; Max Tol: +0.3nH; Maximum Operating Temperature: +125DEGC; Maximum Tolerance: +0.3nH; Min Oper Temp: -55DEGC; Min Tol: -0.3nH; Minimum Operating Temperature: -55DEGC; Minimum Tolerance: -0.3nH; Mounting Type: SMD; NOTEfied URL: https://notefied-dynamic-precision.com/NOTEfiedWebInterface/part/show?partNumber=03-06630; PCB Package: 0402; Packing Size: 10000; Packing Type: Tape & Reel; Part Number: 03-06630; Part Type: Inductor|RF|CHIP|0402; REACH/SVHC Compliance: Compliant; REACH/SVHC Details: SVHC List Version Jul 7, 2017; REACH/SVHC Source: REACH Declaration; REACH/SVHC Status: Unaffected; REACH/SVHC_COMPLIANCE: COMPLIANT; REACH/SVHC_DETAILS: SVHC LIST VERSION Jun 20, 2016; REACH/SVHC_SOURCE: REACH DECLARATION; REACH/SVHC_STATUS: UNAFFECTED; ROHS: Compliant; Revision: R026; RoHS Status: ROHS_COMPLIANT; Rtd Current: 0.3A; Status: Released; Texas Part Status: Under Review; Type: Inductor; Vendor: MURATA; Vendor Part Number: LQG15HS3N9S02D; Vendor Part Status: Active; Weight: 0.001g
L54 = INDUCTOR_HOR_1_2: INDUCTOR, RF, CHIP, NON-MAGNETIC CORE, 1.5nH, -0.3nH/+0.3nH, 0.3A, -55DEGC/+125DEGC, 0402, SMD; Additional Datasheet URL: https://search.murata.co.jp/Ceramy/image/img/P02/JELF243B-0010.pdf; AutoDoc File: https://notefied-dynamic-precision.com/DB/Apps/Desktop/Item/Object.aspx?id=116041; BU Name: TEXAS INSTRUMENTS NORWAY; Budget Currency: EUR; Budget Price: 0.031; Budgetary Price: 0.01872 USD; Client Status: UNDER_REVIEW; Core Material: NON-MAGNETIC; Country of Origin: Japan,Singapore; Datasheet URL: https://www.murata.com/-/media/webrenewal/support/library/catalog/products/inductor/chip/o05e.ashx?la=en-gb; Datasheet URL 1: http://psearch.murata.com/inductor/product/LQG15HS1N0S02%23.pdf; Datasheet URL 2: http://www.murata.com/~/media/webrenewal/support/library/catalog/products/inductor/chip/o05e.ashx; Frequency: 6GHz; Lead Time: 8; Mass: 0.001g; Max Oper Temp: +125DEGC; Max Tol: +0.3nH; Maximum Operating Temperature: +125DEGC; Maximum Tolerance: +0.3nH; Min Oper Temp: -55DEGC; Min Tol: -0.3nH; Minimum Operating Temperature: -55DEGC; Minimum Tolerance: -0.3nH; Mounting Type: SMD; NOTEfied URL: https://notefied-dynamic-precision.com/NOTEfiedWebInterface/part/show?partNumber=03-07531; PCB Package: 0402; Packing Size: 10000; Packing Type: Tape & Reel; Part Number: 03-07531; Part Type: Inductor|RF|CHIP|0402; REACH/SVHC Compliance: Compliant; REACH/SVHC Details: SVHC List Version Jul 7, 2017; REACH/SVHC Source: REACH Declaration; REACH/SVHC Status: Unaffected; REACH/SVHC_COMPLIANCE: COMPLIANT; REACH/SVHC_DETAILS: SVHC LIST VERSION Jun 20, 2016; REACH/SVHC_SOURCE: REACH DECLARATION; REACH/SVHC_STATUS: UNAFFECTED; ROHS: Compliant; Resistance: 0.1; Revision: R028; RoHS Status: ROHS_COMPLIANT; Rtd Current: 0.3A; Status: Released; Texas Part Status: Under Review; Type: Inductor; Vendor: MURATA; Vendor Part Number: LQG15HS1N5S02D; Vendor Part Status: Active; Weight: 0.001g
L331 = INDUCTOR: INDUCTOR, STANDARD, FERRITE CORE, 6.8uH, -20%/+20%, 0.11A, -55DEGC/+125DEGC, 0805, SMD; ALT_SYMBOLS: INDC2012X150A2L,INDC2012X150A2M; Additional Datasheet URL: https://product.tdk.com/en/search/inductor/inductor/smd/info?part_no=MLZ2012N6R8LT000; AutoDoc File: https://notefied-dynamic-precision.com/DB/Apps/Desktop/Item/Object.aspx?id=102853; BU Name: DYNAMIC PRECISION GDANSK; Budget Currency: EUR; Budget Price: 0.059; Budgetary Price: 0.045 USD; Client Status: UNDER_REVIEW; Core Material: FERRITE; Country of Origin: Missing Info; Datasheet URL: http://product.tdk.com/info/en/catalog/datasheets/inductor_commercial_decoupling_mlz2012_en.pdf; Datasheet URL 1: https://product.tdk.com/info/en/catalog/datasheets/inductor_commercial_decoupling_mlz2012_en.pdf; Datasheet URL 2: N/A; Lead Time: 10; MPN: MLZ2012N6R8LT000; MPN Status: ACTIVE; Manufacturer: TDK; Mass: 0.01g; Max Oper Temp: +125DEGC; Max Tol: +20%; Maximum Operating Temperature: +125DEGC; Maximum Tolerance: +20%; Min Oper Temp: -55DEGC; Min Tol: -20%; Minimum Operating Temperature: -55DEGC; Minimum Tolerance: -20%; Mounting Type: SMD; NOTE Status: PREFERRED; NOTEfied URL: https://notefied-dynamic-precision.com/NOTEfiedWebInterface/part/show?partNumber=03-07266; Old Footprint: INDC2012X150N; PCB Package: 0805; Packing Size: 4000; Packing Type: Tape & Reel; Part Number: 03-07266; Part Type: Inductor|STANDARD|CHIP|0805; REACH/SVHC Compliance: Compliant; REACH/SVHC Details: SVHC List Version Jan 12, 2017; REACH/SVHC Source: REACH Declaration; REACH/SVHC Status: Unaffected; REACH/SVHC_COMPLIANCE: COMPLIANT; REACH/SVHC_DETAILS: SVHC LIST VERSION Dec 17, 2015; REACH/SVHC_SOURCE: REACH DECLARATION; REACH/SVHC_STATUS: UNAFFECTED; ROHS: Compliant; Resistance: 0.25; Revision: R020; RoHS Status: ROHS_COMPLIANT; Rtd Current: 1.1A; Status: Released; Texas Part Status: Under Review; Type: Inductor; Vendor: TDK; Vendor Part Number: MLZ2012N6R8LT000; Vendor Part Status: Active; WEIGHT: 0.01g
L332 = INDUCTOR_HOR_1_2: INDUCTOR, RF, CHIP, NON-MAGNETIC CORE, 2nH, -0.3nH/+0.3nH, 0.3A, -55DEGC/+125DEGC, 0402, SMD; Additional Datasheet URL: https://search.murata.co.jp/Ceramy/image/img/P02/JELF243B-0010.pdf; AutoDoc File: https://notefied-dynamic-precision.com/DB/Apps/Desktop/Item/Object.aspx?id=113364; BU Name: TEXAS INSTRUMENTS NORWAY; Budget Currency: EUR; Budget Price: 0.031; Budgetary Price: 0.01872 USD; Client Status: UNDER_REVIEW; Core Material: NON-MAGNETIC; Country of Origin: Japan,Singapore; Datasheet URL: https://www.murata.com/-/media/webrenewal/support/library/catalog/products/inductor/chip/o05e.ashx?la=en-gb; Datasheet URL 1: http://psearch.murata.com/inductor/product/LQG15HS2N0S02%23.pdf; Datasheet URL 2: http://www.murata.com/~/media/webrenewal/support/library/catalog/products/inductor/chip/o05e.ashx; Exclusive for Customers: TEXAS INSTRUMENTS NORWAY; Frequency: 6GHz; Lead Time: 8; Mass: 0.001g; Max Oper Temp: +125DEGC; Max Tol: +0.3nH; Maximum Operating Temperature: +125DEGC; Maximum Tolerance: +0.3nH; Min Oper Temp: -55DEGC; Min Tol: -0.3nH; Minimum Operating Temperature: -55DEGC; Minimum Tolerance: -0.3nH; Mounting Type: SMD; NOTEfied URL: https://notefied-dynamic-precision.com/NOTEfiedWebInterface/part/show?partNumber=03-07527; Notes: Standard item: Duplicate Reason: custom footprint for TEXAS INSTRUMENTS NORWAY.; PCB Package: 0402; Packing Size: 10000; Packing Type: Tape & Reel; Part Number: 03-07527; Part Type: Inductor|RF|CHIP|0402; REACH/SVHC Compliance: Compliant; REACH/SVHC Details: SVHC List Version Jul 7, 2017; REACH/SVHC Source: REACH Declaration; REACH/SVHC Status: Unaffected; REACH/SVHC_COMPLIANCE: COMPLIANT; REACH/SVHC_DETAILS: SVHC LIST VERSION Dec 17, 2015; REACH/SVHC_SOURCE: REACH DECLARATION; REACH/SVHC_STATUS: UNAFFECTED; ROHS: Compliant; Revision: R024; RoHS Status: ROHS_COMPLIANT; Rtd Current: 0.3A; Status: Released; Texas Part Status: Under Review; Type: Inductor; Vendor: MURATA; Vendor Part Number: LQG15HS2N0S02D; Vendor Part Status: Active; Weight: 0.001g
P1 P2 = CONN_HEADER_2X10_P_S: CONNECTOR, HEADER, FEMALE, STRAIGHT, 2 ROWS, 20 PINS, PITCH 1.27mm, SMD; ALT_SYMBOLS: SAMTEC_SFM11002AL,SAMTEC_SFM11002AM; Additional Datasheet URL: http://suddendocs.samtec.com/prints/sfm-1xx-xx-xxx-d-xxx-mkt.pdf; Alt IPC Footprints: SAMTEC_SFM11002AL,SAMTEC_SFM11002AM; AutoDoc File: https://notefied-dynamic-precision.com/DB/Apps/Desktop/Item/Object.aspx?id=85603; BU Name: TEXAS INSTRUMENTS NORWAY; Budget Currency: USD; Budget Price: 3.180; Budgetary Price: 5.3504 USD; CLASS: IO; Client Status: UNDER_REVIEW; Country of Origin: China,Costa Rica,Malaysia,Singapore,United States; Datasheet URL: http://suddendocs.samtec.com/catalog_english/sfm.pdf; Datasheet URL 1: http://suddendocs.samtec.com/catalog_english/sfm.pdf; Datasheet URL 2: http://suddendocs.samtec.com/prints/sfm-1xx-xx-xxx-d-xxx-mkt.pdf; MPN: SFM-110-02-SM-D-A-K-TR; MPN Status: ACTIVE; Manufacturer: SAMTEC; Mass: 0.30875g; Max Oper Temp: +125DEGC; Maximum Operating Temperature: +125DEGC; Min Oper Temp: -55DEGC; Minimum Operating Temperature: -55DEGC; Mounting Type: SMD; NOTE Status: PREFERRED; NOTEfied URL: https://notefied-dynamic-precision.com/NOTEfiedWebInterface/part/show?partNumber=06-02251; No Of Pos: 20; No Of Rows: 2; Number of Positions: 20; Number of Rows: 2; Packing Size: 725; Packing Type: Tape & Reel; Part Number: 06-02251; Part Type: Connector|HEADER|STANDARD; Pitch: 1.27mm; REACH/SVHC Compliance: Compliant; REACH/SVHC Details: SVHC List Version Jan 12, 2017; REACH/SVHC Source: Material Declaration; REACH/SVHC Status: Unaffected; ROHS: Compliant; Revision: R018; RoHS Status: ROHS_COMPLIANT; Status: Released; Texas Part Status: Under Review; Type: Connector; Vendor: SAMTEC; Vendor Part Number: SFM-110-02-SM-D-A-K-TR; Vendor Part Status: Active; Weight: 0.30875g
R351 = RESISTOR: RESISTOR, THICK FILM, 100k, -5%/+5%, 0.063W, 50V, -55DEGC/+155DEGC, 0402, SMD; Additional Datasheet URL: N/A; AutoDoc File: https://notefied-dynamic-precision.com/DB/Apps/Desktop/Item/Object.aspx?id=114565; BU Name: TEXAS INSTRUMENTS NORWAY; Budget Currency: EUR; Budget Price: 0.014; Budgetary Price: 0.014 EUR; Client Status: UNDER_REVIEW; Country of Origin: United States; Datasheet URL: https://www.vishay.com/docs/20035/dcrcwe3.pdf; Datasheet URL 1: http://www.vishay.com/docs/20035/dcrcwe3.pdf; Datasheet URL 2: N/A; Definied Quality: INDUSTRIAL; Esd Level: N/A; Exclusive for Customers: TEXAS INSTRUMENTS NORWAY; Lead Time: 18; LifeCycle Status: ACTIVE; MPN: RESISTOR_0402_100k_+/-1%_50V_0.063W_M_+/-100PPM; MPN Status: ACTIVE; MSL: N/A; MTBF: N/A; MTBF Standard: N/A; Manufacturer: MANUFACTURER SELECTION; Mass: 0.00065g; Max Oper Temp: +155DEGC; Max TC: +200PPM/DEGC; Max Tol: +5%; Maximum Operating Temperature: +155DEGC; Maximum Temperature Coefficient: +200PPM/DEGC; Maximum Tolerance: +5%; Min Oper Temp: -55DEGC; Min TC: -200PPM/DEGC; Min Tol: -5%; Minimum Operating Temperature: -55DEGC; Minimum Temperature Coeficient: -200PPM/DEGC; Minimum Tolerance: -5%; Mounting Type: SMD; NOTE Status: PREFERRED; NOTEfied URL: https://notefied-dynamic-precision.com/NOTEfiedWebInterface/part/show?partNumber=01-22492; Notes: Standard item: Duplicate Reason: custom footprint for TEXAS INSTRUMENTS NORWAY.; Old Footprint: RESC1005X40N; PCB Package: 0402; Packing Size: 10000; Packing Type: Tape & Reel; Part Number: 01-22492; Part Type: Resistor|0402|STANDARD; REACH/SVHC Compliance: Compliant; REACH/SVHC Details: SVHC List Version Jun 20, 2016; REACH/SVHC Source: Material Declaration; REACH/SVHC Status: Unaffected; REACH/SVHC_COMPLIANCE: COMPLIANT; REACH/SVHC_DETAILS: SVHC LIST VERSION Jun 20, 2016; REACH/SVHC_SOURCE: MATERIAL DECLARATION; REACH/SVHC_STATUS: UNAFFECTED; ROHS: Exempt; Rated Current: N/A; Rated Power: 0.063W; Rated Voltage: 50V; Resistor Type: THICK FILM; Revision: R020; RoHS Status: ROHS_COMPLIANT; Rtd Current: N/A; Rtd Power: 0.063W; Rtd Voltage: 50V; Status: Released; Texas Part Status: Under Review; Type: Resistor; Vendor: VISHAY; Vendor Part Number: CRCW0402100KJNED; Vendor Part Status: Active; WEIGHT: 0.00065g
U1 = IC_RF_CC2651P1F32TRKPR_VQFN40: IC, MICROCONTROLLER, TEXAS INSTRUMENTS, ARM CORTEX M4F, MULTIPROTOCOL 2.4 GHZ WIRELESS MCU WITH INTEGRATED POWER AMPLIFIER, 1.8V TO 3.8V, VQFN40-EP, SMD; ALT_SYMBOLS: QFNFC40P500X500X100-41A2L,QFNFC40P500X500X100-41A2M; Additional Datasheet URL: N/A; Datasheet URL: https://www.ti.com/; Exclusive for Customers: TEXAS INSTRUMENTS NORWAY; Frequency: 48MHz; Mass: N/A; Maximum Operating Temperature: +85DEGC; Minimum Operating Temperature: -40DEGC; Mounting Type: SMD; NOTEfied URL: https://notefied-dynamic-precision.com/NOTEfiedWebInterface/part/show?partNumber=18-36303; Notes: Preliminary item, please check if it apperas on the website.; PCB Package: VQFN40-EP; Packing Size: N/A; Packing Type: Missing Info; Part Number: 18-36303; Part Type: IC|MICROCONTROLLER|TEXAS INSTRUMENTS; REACH/SVHC Compliance: Missing Info; REACH/SVHC Details: N/A; REACH/SVHC Source: N/A; REACH/SVHC Status: Missing Info; ROHS: Compliant; Rated Voltage: 1.8V TO 3.8V; Revision: R002; Status: Released; Texas Part Status: Under Review; Type: IC; Vendor: TEXAS INSTRUMENTS; Vendor Part Status: Preliminary
Y1 = XTAL: CRYSTAL, RESONATOR, 32.768kHz, -40DEGC/+125DEGC, SMD; ALT_SYMBOLS: XTAL_TZ1166C_B2L,XTAL_TZ1166C_B2M; Additional Datasheet URL: N/A; Capacitance: 7pF; Datasheet URL: https://www.taisaw.com/en/product.php?pc=7; Exclusive for Customers: TEXAS INSTRUMENTS NORWAY; Mass: N/A; Maximum Operating Temperature: +125DEGC; Maximum Stability: N/A; Maximum Tolerance: +20PPM; Minimum Operating Temperature: -40DEGC; Minimum Stability: N/A; Minimum Tolerance: -20PPM; Mounting Type: SMD; NOTEfied URL: https://notefied-dynamic-precision.com/NOTEfiedWebInterface/part/show?partNumber=12-01495; Notes: Non-standard part/non-catalogue part. Created on the basis of documentation provided by the customer (Texas Instruments).; Packing Size: 3000; Packing Type: Tape & Reel; Part Number: 12-01495; Part Type: Crystal|RESONATOR; REACH/SVHC Compliance: Missing Info; REACH/SVHC Details: N/A; REACH/SVHC Source: N/A; REACH/SVHC Status: Missing Info; ROHS: Compliant; Revision: R003; Status: Released; Texas Part Status: Under Review; Type: Crystal; Vendor: TAI-SAW; Vendor Part Number: TZ1166C; Vendor Part Status: Active
Y2 = XTAL_4_V3: CRYSTAL, RESONATOR, 48MHz, -16PPM/+16PPM, -40DEGC/+105DEGC, SMD; ALT_SYMBOLS: OSCCC200X160X50-4A2L,OSCCC200X160X50-4A2M; Additional Datasheet URL: N/A; Capacitance: 7pF; Datasheet URL: https://www.taisaw.com/en/product.php?pc=7; Exclusive for Customers: TEXAS INSTRUMENTS NORWAY; Mass: 0.0057g; Maximum Operating Temperature: +105DEGC; Maximum Stability: +16PPM; Maximum Tolerance: +8PPM; Minimum Operating Temperature: -40DEGC; Minimum Stability: -16PPM; Minimum Tolerance: -8PPM; Mounting Type: SMD; NOTEfied URL: https://notefied-dynamic-precision.com/NOTEfiedWebInterface/part/show?partNumber=12-01494; Notes: Non-standard part/non-catalogue part. Created on the basis of documentation provided by the customer (Texas Instruments).; Packing Size: 3000; Packing Type: Tape & Reel; Part Number: 12-01494; Part Type: Crystal|RESONATOR; REACH/SVHC Compliance: Missing Info; REACH/SVHC Details: N/A; REACH/SVHC Source: N/A; REACH/SVHC Status: Missing Info; ROHS: Compliant; Revision: R002; Status: Released; Texas Part Status: Under Review; Type: Crystal; Vendor: TAI-SAW; Vendor Part Number: TZ2365C; Vendor Part Status: Active

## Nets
GND: C1.2 C51.1 C52.2 C54.2 C55.2 C56.2 C61.1 C81.2 C91.2 C131.2 C221.2 C231.2 C331.2 C341.2 C342.2 C351.2 C441.2 C451.2 C461.2 C471.2 C481.2 C482.1 C483.1 J1.2 J1.3 J1.4 J1.5 J2.2 J2.3 J2.4 J2.5 P1.1 P1.19 P2.2 P2.20 U1.41(EGP) Y2.2(GND) Y2.4(GND) ; also on sheet 1
VDD_EB: FL1.2 P2.7 P2.9
VDDR: C51.2 C52.1 C331.1 C451.1 C481.1 L52.1 L331.2 U1.37(VDDR_1/2) U1.40(VDDR_3/4)
VDDS: C1.1 C131.1 C221.1 C341.1 C342.1 C441.1 FL1.1 R351.2 U1.13(VDDS2) U1.16(VDDS3) U1.26(VDDA1/2) U1.36(VDDA3_VDDS1)
DCDC_SW: L331.1 U1.25(DCDC_SW)
DIO_5: P1.13 U1.10(DIO_5)
DIO_6: P1.4 U1.11(DIO_6)
DIO_7: P1.2 U1.12(DIO_7)
DIO_8: P1.20 U1.14(DIO_8)
DIO_9: P1.18 U1.15(DIO_9)
DIO_10: P1.16 U1.20(DIO_10)
DIO_11: P1.14 U1.21(DIO_11)
DIO_12: P1.12 U1.22(DIO_12)
DIO_13: P1.15 U1.23(DIO_13)
DIO_14: P1.17 U1.24(DIO_14)
DIO_15: P1.6 U1.28(DIO_15)
DIO_16 / JTAG TDO: P2.19 U1.29(DIO_16)
DIO_17 / JTAG TDI: P2.17 U1.30(DIO_17)
DIO_18: P1.7 U1.31(DIO_18)
DIO_19: P1.9 U1.32(DIO_19)
DIO_20: P2.8 U1.33(DIO_20)
DIO_21: P2.18 U1.34(DIO_21)
DIO_22: P1.3 U1.35(DIO_22)
JTAG_TCK: P2.1 U1.19(JTAG_TCKC)
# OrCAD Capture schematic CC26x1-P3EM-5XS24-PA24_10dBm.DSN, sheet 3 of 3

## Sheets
3 Revision

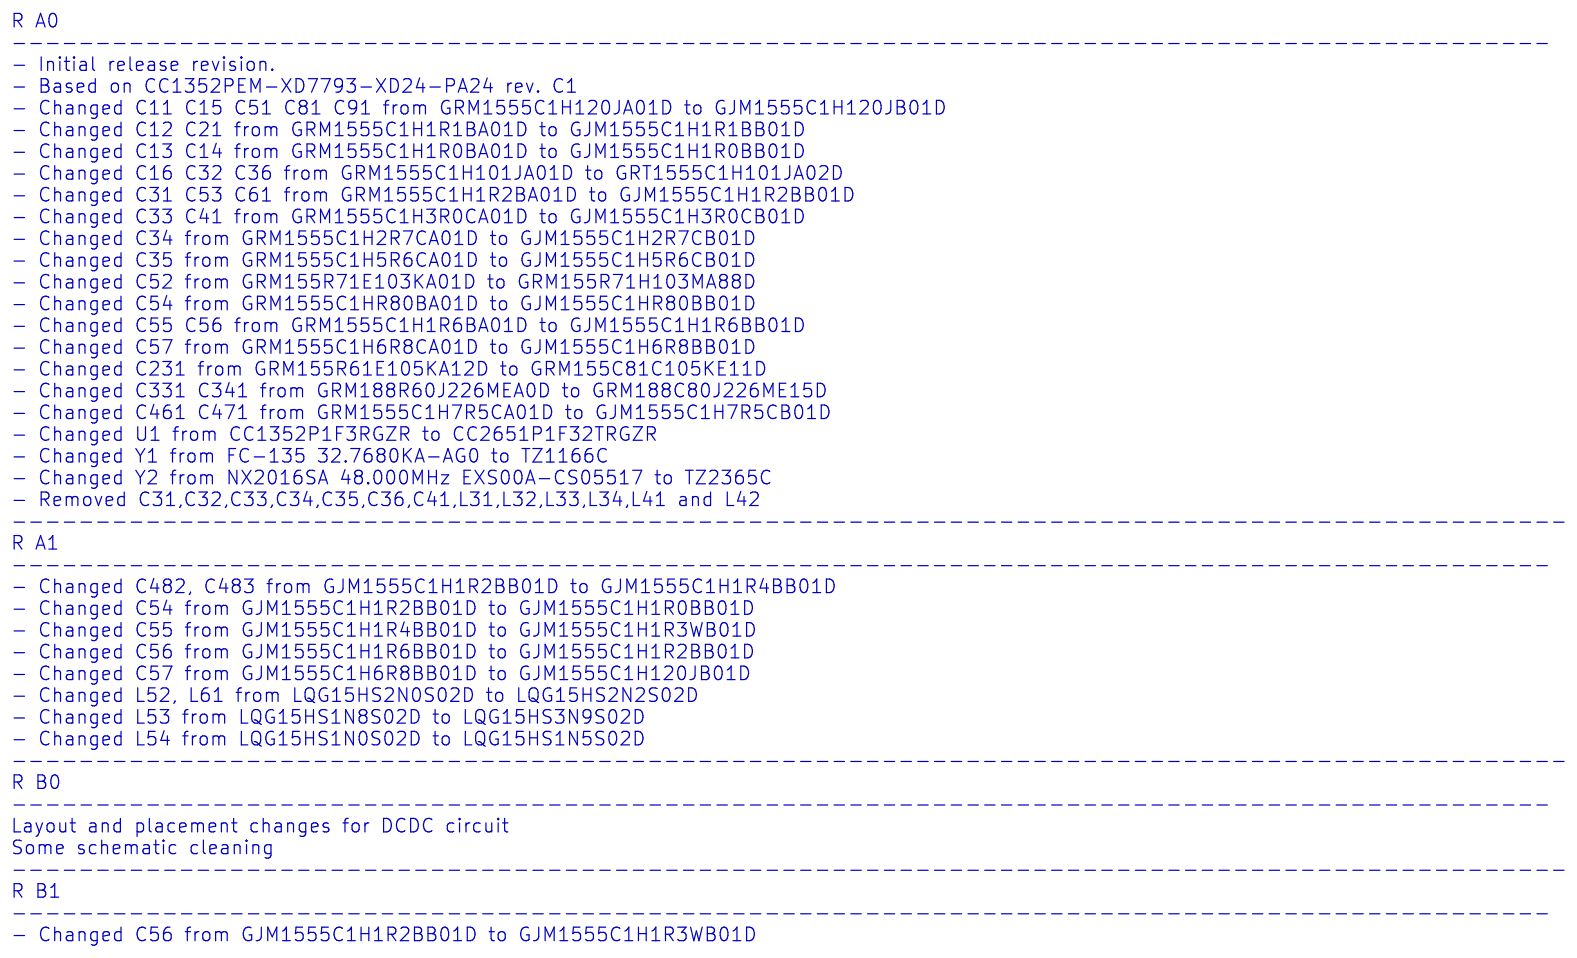
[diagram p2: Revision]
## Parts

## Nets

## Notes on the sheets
sheet 3
- R A0
  --------------------------------------------------------------------------------------------
  - Initial release revision.
  - Based on CC1352PEM-XD7793-XD24-PA24 rev. C1
  - Changed C11 C15 C51 C81 C91 from GRM1555C1H120JA01D to GJM1555C1H120JB01D
  - Changed C12 C21 from GRM1555C1H1R1BA01D to GJM1555C1H1R1BB01D
  - Changed C13 C14 from GRM1555C1H1R0BA01D to GJM1555C1H1R0BB01D
  - Changed C16 C32 C36 from GRM1555C1H101JA01D to GRT1555C1H101JA02D
  - Changed C31 C53 C61 from GRM1555C1H1R2BA01D to GJM1555C1H1R2BB01D
  - Changed C33 C41 from GRM1555C1H3R0CA01D to GJM1555C1H3R0CB01D
  - Changed C34 from GRM1555C1H2R7CA01D to GJM1555C1H2R7CB01D
  - Changed C35 from GRM1555C1H5R6CA01D to GJM1555C1H5R6CB01D
  - Changed C52 from GRM155R71E103KA01D to GRM155R71H103MA88D
  - Changed C54 from GRM1555C1HR80BA01D to GJM1555C1HR80BB01D
  - Changed C55 C56 from GRM1555C1H1R6BA01D to GJM1555C1H1R6BB01D
  - Changed C57 from GRM1555C1H6R8CA01D to GJM1555C1H6R8BB01D
  - Changed C231 from GRM155R61E105KA12D to GRM155C81C105KE11D
  - Changed C331 C341 from GRM188R60J226MEA0D to GRM188C80J226ME15D
  - Changed C461 C471 from GRM1555C1H7R5CA01D to GJM1555C1H7R5CB01D
  - Changed U1 from CC1352P1F3RGZR to CC2651P1F32TRGZR
  - Changed Y1 from FC-135 32.7680KA-AG0 to TZ1166C
  - Changed Y2 from NX2016SA 48.000MHz EXS00A-CS05517 to TZ2365C
  - Removed C31,C32,C33,C34,C35,C36,C41,L31,L32,L33,L34,L41 and L42
  ---------------------------------------------------------------------------------------------
  R A1
  --------------------------------------------------------------------------------------------
  - Changed C482, C483 from GJM1555C1H1R2BB01D to GJM1555C1H1R4BB01D
  - Changed C54 from GJM1555C1H1R2BB01D to GJM1555C1H1R0BB01D
  - Changed C55 from GJM1555C1H1R4BB01D to GJM1555C1H1R3WB01D
  - Changed C56 from GJM1555C1H1R6BB01D to GJM1555C1H1R2BB01D
  - Changed C57 from GJM1555C1H6R8BB01D to GJM1555C1H120JB01D
  - Changed L52, L61 from LQG15HS2N0S02D to LQG15HS2N2S02D
  - Changed L53 from LQG15HS1N8S02D to LQG15HS3N9S02D
  - Changed L54 from LQG15HS1N0S02D to LQG15HS1N5S02D
  ---------------------------------------------------------------------------------------------
  R B0
  --------------------------------------------------------------------------------------------
  Layout and placement changes for DCDC circuit
  Some schematic cleaning
  ---------------------------------------------------------------------------------------------
  R B1
  --------------------------------------------------------------------------------------------
  - Changed C56 from GJM1555C1H1R2BB01D to GJM1555C1H1R3WB01D
